VERSION 5.4 ;
NAMESCASESENSITIVE ON ;
BUSBITCHARS "[]" ;
DIVIDERCHAR "/" ;
UNITS
  DATABASE MICRONS 1000 ;
END UNITS
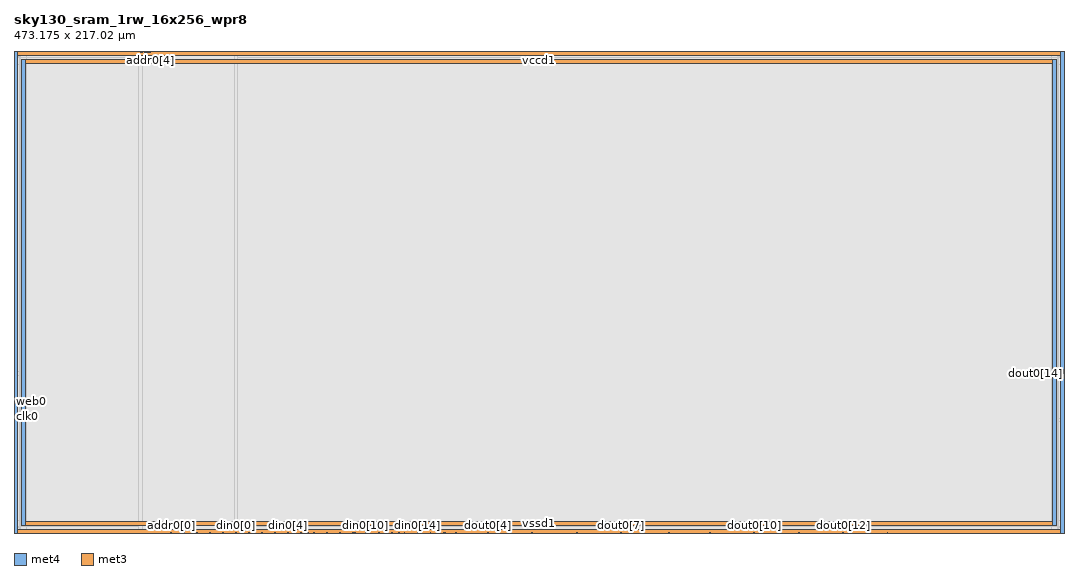
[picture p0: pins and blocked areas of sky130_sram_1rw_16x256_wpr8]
MACRO sky130_sram_1rw_16x256_wpr8
   CLASS BLOCK ;
   SIZE 473.175 BY 217.02 ;
   SYMMETRY X Y R90 ;
   PIN din0[0]
      DIRECTION INPUT ;
      PORT
         LAYER met4 ;
         RECT  99.9 0.0 100.28 0.38 ;
      END
   END din0[0]
   PIN din0[1]
      DIRECTION INPUT ;
      PORT
         LAYER met4 ;
         RECT  105.74 0.0 106.12 0.38 ;
      END
   END din0[1]
   PIN din0[2]
      DIRECTION INPUT ;
      PORT
         LAYER met4 ;
         RECT  111.58 0.0 111.96 0.38 ;
      END
   END din0[2]
   PIN din0[3]
      DIRECTION INPUT ;
      PORT
         LAYER met4 ;
         RECT  117.42 0.0 117.8 0.38 ;
      END
   END din0[3]
   PIN din0[4]
      DIRECTION INPUT ;
      PORT
         LAYER met4 ;
         RECT  123.26 0.0 123.64 0.38 ;
      END
   END din0[4]
   PIN din0[5]
      DIRECTION INPUT ;
      PORT
         LAYER met4 ;
         RECT  129.1 0.0 129.48 0.38 ;
      END
   END din0[5]
   PIN din0[6]
      DIRECTION INPUT ;
      PORT
         LAYER met4 ;
         RECT  134.94 0.0 135.32 0.38 ;
      END
   END din0[6]
   PIN din0[7]
      DIRECTION INPUT ;
      PORT
         LAYER met4 ;
         RECT  140.78 0.0 141.16 0.38 ;
      END
   END din0[7]
   PIN din0[8]
      DIRECTION INPUT ;
      PORT
         LAYER met4 ;
         RECT  146.62 0.0 147.0 0.38 ;
      END
   END din0[8]
   PIN din0[9]
      DIRECTION INPUT ;
      PORT
         LAYER met4 ;
         RECT  152.46 0.0 152.84 0.38 ;
      END
   END din0[9]
   PIN din0[10]
      DIRECTION INPUT ;
      PORT
         LAYER met4 ;
         RECT  158.3 0.0 158.68 0.38 ;
      END
   END din0[10]
   PIN din0[11]
      DIRECTION INPUT ;
      PORT
         LAYER met4 ;
         RECT  164.14 0.0 164.52 0.38 ;
      END
   END din0[11]
   PIN din0[12]
      DIRECTION INPUT ;
      PORT
         LAYER met4 ;
         RECT  169.98 0.0 170.36 0.38 ;
      END
   END din0[12]
   PIN din0[13]
      DIRECTION INPUT ;
      PORT
         LAYER met4 ;
         RECT  175.82 0.0 176.2 0.38 ;
      END
   END din0[13]
   PIN din0[14]
      DIRECTION INPUT ;
      PORT
         LAYER met4 ;
         RECT  181.66 0.0 182.04 0.38 ;
      END
   END din0[14]
   PIN din0[15]
      DIRECTION INPUT ;
      PORT
         LAYER met4 ;
         RECT  187.5 0.0 187.88 0.38 ;
      END
   END din0[15]
   PIN din0[16]
      DIRECTION INPUT ;
      PORT
         LAYER met4 ;
         RECT  193.34 0.0 193.72 0.38 ;
      END
   END din0[16]
   PIN addr0[0]
      DIRECTION INPUT ;
      PORT
         LAYER met4 ;
         RECT  70.7 0.0 71.08 0.38 ;
      END
   END addr0[0]
   PIN addr0[1]
      DIRECTION INPUT ;
      PORT
         LAYER met4 ;
         RECT  76.54 0.0 76.92 0.38 ;
      END
   END addr0[1]
   PIN addr0[2]
      DIRECTION INPUT ;
      PORT
         LAYER met4 ;
         RECT  82.38 0.0 82.76 0.38 ;
      END
   END addr0[2]
   PIN addr0[3]
      DIRECTION INPUT ;
      PORT
         LAYER met4 ;
         RECT  56.79 216.64 57.17 217.02 ;
      END
   END addr0[3]
   PIN addr0[4]
      DIRECTION INPUT ;
      PORT
         LAYER met4 ;
         RECT  61.145 216.64 61.525 217.02 ;
      END
   END addr0[4]
   PIN addr0[5]
      DIRECTION INPUT ;
      PORT
         LAYER met4 ;
         RECT  57.48 216.64 57.86 217.02 ;
      END
   END addr0[5]
   PIN addr0[6]
      DIRECTION INPUT ;
      PORT
         LAYER met4 ;
         RECT  60.455 216.64 60.835 217.02 ;
      END
   END addr0[6]
   PIN addr0[7]
      DIRECTION INPUT ;
      PORT
         LAYER met4 ;
         RECT  59.765 216.64 60.145 217.02 ;
      END
   END addr0[7]
   PIN addr0[8]
      DIRECTION INPUT ;
      PORT
         LAYER met4 ;
         RECT  59.02 216.64 59.4 217.02 ;
      END
   END addr0[8]
   PIN csb0
      DIRECTION INPUT ;
      PORT
         LAYER met3 ;
         RECT  0.0 50.785 0.38 51.165 ;
      END
   END csb0
   PIN web0
      DIRECTION INPUT ;
      PORT
         LAYER met3 ;
         RECT  0.0 59.185 0.38 59.565 ;
      END
   END web0
   PIN clk0
      DIRECTION INPUT ;
      PORT
         LAYER met3 ;
         RECT  0.0 52.275 0.38 52.655 ;
      END
   END clk0
   PIN wmask0[0]
      DIRECTION INPUT ;
      PORT
         LAYER met4 ;
         RECT  88.22 0.0 88.6 0.38 ;
      END
   END wmask0[0]
   PIN wmask0[1]
      DIRECTION INPUT ;
      PORT
         LAYER met4 ;
         RECT  94.06 0.0 94.44 0.38 ;
      END
   END wmask0[1]
   PIN spare_wen0
      DIRECTION INPUT ;
      PORT
         LAYER met4 ;
         RECT  199.18 0.0 199.56 0.38 ;
      END
   END spare_wen0
   PIN dout0[0]
      DIRECTION OUTPUT ;
      PORT
         LAYER met4 ;
         RECT  132.155 0.0 132.535 0.38 ;
      END
   END dout0[0]
   PIN dout0[1]
      DIRECTION OUTPUT ;
      PORT
         LAYER met4 ;
         RECT  153.42 0.0 153.8 0.38 ;
      END
   END dout0[1]
   PIN dout0[2]
      DIRECTION OUTPUT ;
      PORT
         LAYER met4 ;
         RECT  173.42 0.0 173.8 0.38 ;
      END
   END dout0[2]
   PIN dout0[3]
      DIRECTION OUTPUT ;
      PORT
         LAYER met4 ;
         RECT  194.03 0.0 194.41 0.38 ;
      END
   END dout0[3]
   PIN dout0[4]
      DIRECTION OUTPUT ;
      PORT
         LAYER met4 ;
         RECT  213.42 0.0 213.8 0.38 ;
      END
   END dout0[4]
   PIN dout0[5]
      DIRECTION OUTPUT ;
      PORT
         LAYER met4 ;
         RECT  233.42 0.0 233.8 0.38 ;
      END
   END dout0[5]
   PIN dout0[6]
      DIRECTION OUTPUT ;
      PORT
         LAYER met4 ;
         RECT  253.42 0.0 253.8 0.38 ;
      END
   END dout0[6]
   PIN dout0[7]
      DIRECTION OUTPUT ;
      PORT
         LAYER met4 ;
         RECT  273.42 0.0 273.8 0.38 ;
      END
   END dout0[7]
   PIN dout0[8]
      DIRECTION OUTPUT ;
      PORT
         LAYER met4 ;
         RECT  294.8 0.0 295.18 0.38 ;
      END
   END dout0[8]
   PIN dout0[9]
      DIRECTION OUTPUT ;
      PORT
         LAYER met4 ;
         RECT  313.42 0.0 313.8 0.38 ;
      END
   END dout0[9]
   PIN dout0[10]
      DIRECTION OUTPUT ;
      PORT
         LAYER met4 ;
         RECT  333.42 0.0 333.8 0.38 ;
      END
   END dout0[10]
   PIN dout0[11]
      DIRECTION OUTPUT ;
      PORT
         LAYER met4 ;
         RECT  353.42 0.0 353.8 0.38 ;
      END
   END dout0[11]
   PIN dout0[12]
      DIRECTION OUTPUT ;
      PORT
         LAYER met4 ;
         RECT  373.42 0.0 373.8 0.38 ;
      END
   END dout0[12]
   PIN dout0[13]
      DIRECTION OUTPUT ;
      PORT
         LAYER met4 ;
         RECT  393.42 0.0 393.8 0.38 ;
      END
   END dout0[13]
   PIN dout0[14]
      DIRECTION OUTPUT ;
      PORT
         LAYER met3 ;
         RECT  472.795 71.73 473.175 72.11 ;
      END
   END dout0[14]
   PIN dout0[15]
      DIRECTION OUTPUT ;
      PORT
         LAYER met3 ;
         RECT  472.795 73.22 473.175 73.6 ;
      END
   END dout0[15]
   PIN dout0[16]
      DIRECTION OUTPUT ;
      PORT
         LAYER met3 ;
         RECT  472.795 72.475 473.175 72.855 ;
      END
   END dout0[16]
   PIN vccd1
      DIRECTION INOUT ;
      USE POWER ; 
      SHAPE ABUTMENT ; 
      PORT
         LAYER met4 ;
         RECT  471.435 0.0 473.175 217.02 ;
         LAYER met3 ;
         RECT  0.0 215.28 473.175 217.02 ;
         LAYER met4 ;
         RECT  0.0 0.0 1.74 217.02 ;
         LAYER met3 ;
         RECT  0.0 0.0 473.175 1.74 ;
      END
   END vccd1
   PIN vssd1
      DIRECTION INOUT ;
      USE GROUND ; 
      SHAPE ABUTMENT ; 
      PORT
         LAYER met4 ;
         RECT  3.48 3.48 5.22 213.54 ;
         LAYER met3 ;
         RECT  3.48 3.48 469.695 5.22 ;
         LAYER met3 ;
         RECT  3.48 211.8 469.695 213.54 ;
         LAYER met4 ;
         RECT  467.955 3.48 469.695 213.54 ;
      END
   END vssd1
   OBS
   LAYER  met1 ;
      RECT  0.62 0.62 472.555 216.4 ;
   LAYER  met2 ;
      RECT  0.62 0.62 472.555 216.4 ;
   LAYER  met3 ;
      RECT  0.98 50.185 472.555 51.765 ;
      RECT  0.62 53.255 0.98 58.585 ;
      RECT  0.98 51.765 472.195 71.13 ;
      RECT  0.98 71.13 472.195 72.71 ;
      RECT  472.195 51.765 472.555 71.13 ;
      RECT  0.62 60.165 0.98 214.68 ;
      RECT  472.195 74.2 472.555 214.68 ;
      RECT  0.62 2.34 0.98 50.185 ;
      RECT  0.98 2.34 2.88 2.88 ;
      RECT  0.98 2.88 2.88 5.82 ;
      RECT  0.98 5.82 2.88 50.185 ;
      RECT  2.88 2.34 470.295 2.88 ;
      RECT  2.88 5.82 470.295 50.185 ;
      RECT  470.295 2.34 472.555 2.88 ;
      RECT  470.295 2.88 472.555 5.82 ;
      RECT  470.295 5.82 472.555 50.185 ;
      RECT  0.98 72.71 2.88 211.2 ;
      RECT  0.98 211.2 2.88 214.14 ;
      RECT  0.98 214.14 2.88 214.68 ;
      RECT  2.88 72.71 470.295 211.2 ;
      RECT  2.88 214.14 470.295 214.68 ;
      RECT  470.295 72.71 472.195 211.2 ;
      RECT  470.295 211.2 472.195 214.14 ;
      RECT  470.295 214.14 472.195 214.68 ;
   LAYER  met4 ;
      RECT  99.3 0.98 100.88 216.4 ;
      RECT  100.88 0.62 105.14 0.98 ;
      RECT  106.72 0.62 110.98 0.98 ;
      RECT  112.56 0.62 116.82 0.98 ;
      RECT  118.4 0.62 122.66 0.98 ;
      RECT  124.24 0.62 128.5 0.98 ;
      RECT  135.92 0.62 140.18 0.98 ;
      RECT  141.76 0.62 146.02 0.98 ;
      RECT  147.6 0.62 151.86 0.98 ;
      RECT  159.28 0.62 163.54 0.98 ;
      RECT  165.12 0.62 169.38 0.98 ;
      RECT  176.8 0.62 181.06 0.98 ;
      RECT  182.64 0.62 186.9 0.98 ;
      RECT  188.48 0.62 192.74 0.98 ;
      RECT  71.68 0.62 75.94 0.98 ;
      RECT  77.52 0.62 81.78 0.98 ;
      RECT  56.19 0.98 57.77 216.04 ;
      RECT  57.77 0.98 99.3 216.04 ;
      RECT  62.125 216.04 99.3 216.4 ;
      RECT  83.36 0.62 87.62 0.98 ;
      RECT  89.2 0.62 93.46 0.98 ;
      RECT  95.04 0.62 99.3 0.98 ;
      RECT  130.08 0.62 131.555 0.98 ;
      RECT  133.135 0.62 134.34 0.98 ;
      RECT  154.4 0.62 157.7 0.98 ;
      RECT  170.96 0.62 172.82 0.98 ;
      RECT  174.4 0.62 175.22 0.98 ;
      RECT  195.01 0.62 198.58 0.98 ;
      RECT  200.16 0.62 212.82 0.98 ;
      RECT  214.4 0.62 232.82 0.98 ;
      RECT  234.4 0.62 252.82 0.98 ;
      RECT  254.4 0.62 272.82 0.98 ;
      RECT  274.4 0.62 294.2 0.98 ;
      RECT  295.78 0.62 312.82 0.98 ;
      RECT  314.4 0.62 332.82 0.98 ;
      RECT  334.4 0.62 352.82 0.98 ;
      RECT  354.4 0.62 372.82 0.98 ;
      RECT  374.4 0.62 392.82 0.98 ;
      RECT  394.4 0.62 470.835 0.98 ;
      RECT  2.34 0.62 70.1 0.98 ;
      RECT  2.34 216.04 56.19 216.4 ;
      RECT  2.34 0.98 2.88 2.88 ;
      RECT  2.34 2.88 2.88 214.14 ;
      RECT  2.34 214.14 2.88 216.04 ;
      RECT  2.88 0.98 5.82 2.88 ;
      RECT  2.88 214.14 5.82 216.04 ;
      RECT  5.82 0.98 56.19 2.88 ;
      RECT  5.82 2.88 56.19 214.14 ;
      RECT  5.82 214.14 56.19 216.04 ;
      RECT  100.88 0.98 467.355 2.88 ;
      RECT  100.88 2.88 467.355 214.14 ;
      RECT  100.88 214.14 467.355 216.4 ;
      RECT  467.355 0.98 470.295 2.88 ;
      RECT  467.355 214.14 470.295 216.4 ;
      RECT  470.295 0.98 470.835 2.88 ;
      RECT  470.295 2.88 470.835 214.14 ;
      RECT  470.295 214.14 470.835 216.4 ;
   END
END    sky130_sram_1rw_16x256_wpr8
END    LIBRARY
